VERSION 5.8 ;
BUSBITCHARS "[]" ;
DIVIDERCHAR "/" ;

UNITS
  DATABASE MICRONS 1000 ;
END UNITS

MANUFACTURINGGRID 0.005 ;

LAYER met1
  TYPE ROUTING ;
  DIRECTION HORIZONTAL ;
  PITCH 0.2 ;
  WIDTH 0.1 ;
END met1

SITE core
  CLASS CORE ;
  SIZE 0.2 BY 1.0 ;
END core

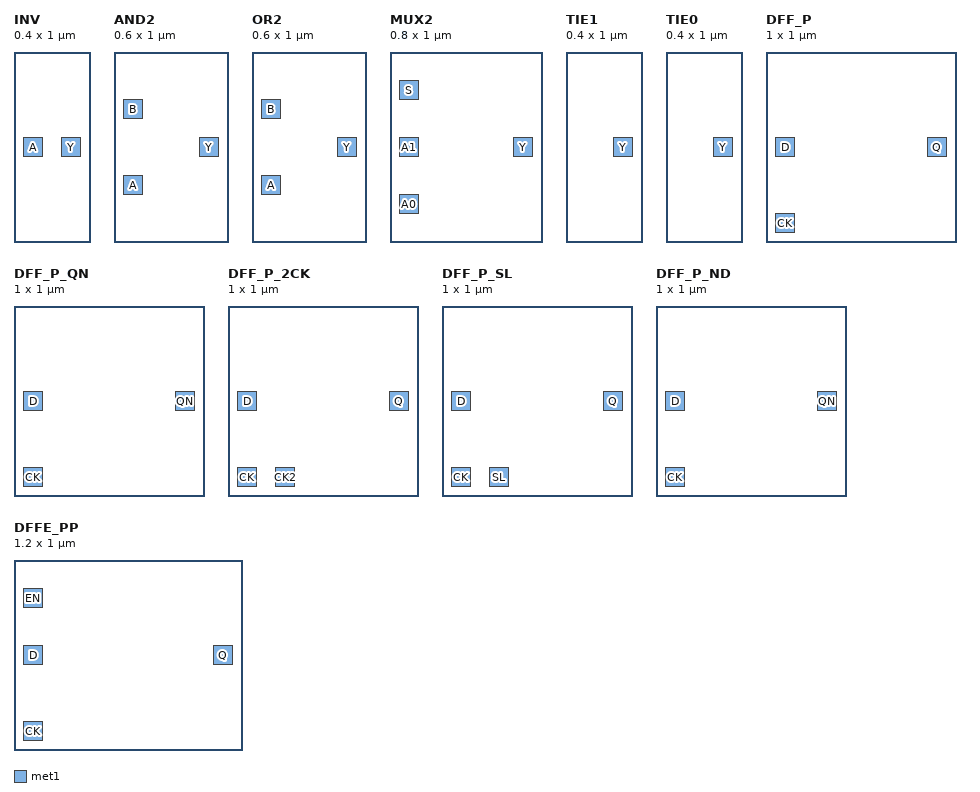
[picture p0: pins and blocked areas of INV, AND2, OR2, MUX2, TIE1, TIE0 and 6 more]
MACRO INV
  CLASS CORE ;
  ORIGIN 0 0 ;
  SIZE 0.4 BY 1.0 ;
  SITE core ;
  PIN A
    DIRECTION INPUT ;
    USE SIGNAL ;
    PORT
      LAYER met1 ;
      RECT 0.05 0.45 0.15 0.55 ;
    END
  END A
  PIN Y
    DIRECTION OUTPUT ;
    USE SIGNAL ;
    PORT
      LAYER met1 ;
      RECT 0.25 0.45 0.35 0.55 ;
    END
  END Y
END INV

MACRO AND2
  CLASS CORE ;
  ORIGIN 0 0 ;
  SIZE 0.6 BY 1.0 ;
  SITE core ;
  PIN A
    DIRECTION INPUT ;
    USE SIGNAL ;
    PORT
      LAYER met1 ;
      RECT 0.05 0.25 0.15 0.35 ;
    END
  END A
  PIN B
    DIRECTION INPUT ;
    USE SIGNAL ;
    PORT
      LAYER met1 ;
      RECT 0.05 0.65 0.15 0.75 ;
    END
  END B
  PIN Y
    DIRECTION OUTPUT ;
    USE SIGNAL ;
    PORT
      LAYER met1 ;
      RECT 0.45 0.45 0.55 0.55 ;
    END
  END Y
END AND2

MACRO OR2
  CLASS CORE ;
  ORIGIN 0 0 ;
  SIZE 0.6 BY 1.0 ;
  SITE core ;
  PIN A
    DIRECTION INPUT ;
    USE SIGNAL ;
    PORT
      LAYER met1 ;
      RECT 0.05 0.25 0.15 0.35 ;
    END
  END A
  PIN B
    DIRECTION INPUT ;
    USE SIGNAL ;
    PORT
      LAYER met1 ;
      RECT 0.05 0.65 0.15 0.75 ;
    END
  END B
  PIN Y
    DIRECTION OUTPUT ;
    USE SIGNAL ;
    PORT
      LAYER met1 ;
      RECT 0.45 0.45 0.55 0.55 ;
    END
  END Y
END OR2
MACRO MUX2
  CLASS CORE ;
  ORIGIN 0 0 ;
  SIZE 0.8 BY 1.0 ;
  SITE core ;
  PIN A0
    DIRECTION INPUT ;
    USE SIGNAL ;
    PORT
      LAYER met1 ;
      RECT 0.05 0.15 0.15 0.25 ;
    END
  END A0
  PIN A1
    DIRECTION INPUT ;
    USE SIGNAL ;
    PORT
      LAYER met1 ;
      RECT 0.05 0.45 0.15 0.55 ;
    END
  END A1
  PIN S
    DIRECTION INPUT ;
    USE SIGNAL ;
    PORT
      LAYER met1 ;
      RECT 0.05 0.75 0.15 0.85 ;
    END
  END S
  PIN Y
    DIRECTION OUTPUT ;
    USE SIGNAL ;
    PORT
      LAYER met1 ;
      RECT 0.65 0.45 0.75 0.55 ;
    END
  END Y
END MUX2


MACRO TIE1
  CLASS CORE ;
  ORIGIN 0 0 ;
  SIZE 0.4 BY 1.0 ;
  SITE core ;
  PIN Y
    DIRECTION OUTPUT ;
    USE SIGNAL ;
    PORT
      LAYER met1 ;
      RECT 0.25 0.45 0.35 0.55 ;
    END
  END Y
END TIE1

MACRO TIE0
  CLASS CORE ;
  ORIGIN 0 0 ;
  SIZE 0.4 BY 1.0 ;
  SITE core ;
  PIN Y
    DIRECTION OUTPUT ;
    USE SIGNAL ;
    PORT
      LAYER met1 ;
      RECT 0.25 0.45 0.35 0.55 ;
    END
  END Y
END TIE0

MACRO DFF_P
  CLASS CORE ;
  ORIGIN 0 0 ;
  SIZE 1.0 BY 1.0 ;
  SITE core ;
  PIN D
    DIRECTION INPUT ;
    USE SIGNAL ;
    PORT
      LAYER met1 ;
      RECT 0.05 0.45 0.15 0.55 ;
    END
  END D
  PIN CK
    DIRECTION INPUT ;
    USE CLOCK ;
    PORT
      LAYER met1 ;
      RECT 0.05 0.05 0.15 0.15 ;
    END
  END CK
  PIN Q
    DIRECTION OUTPUT ;
    USE SIGNAL ;
    PORT
      LAYER met1 ;
      RECT 0.85 0.45 0.95 0.55 ;
    END
  END Q
END DFF_P

MACRO DFF_P_QN
  CLASS CORE ;
  ORIGIN 0 0 ;
  SIZE 1.0 BY 1.0 ;
  SITE core ;
  PIN D
    DIRECTION INPUT ;
    USE SIGNAL ;
    PORT
      LAYER met1 ;
      RECT 0.05 0.45 0.15 0.55 ;
    END
  END D
  PIN CK
    DIRECTION INPUT ;
    USE CLOCK ;
    PORT
      LAYER met1 ;
      RECT 0.05 0.05 0.15 0.15 ;
    END
  END CK
  PIN QN
    DIRECTION OUTPUT ;
    USE SIGNAL ;
    PORT
      LAYER met1 ;
      RECT 0.85 0.45 0.95 0.55 ;
    END
  END QN
END DFF_P_QN

MACRO DFF_P_2CK
  CLASS CORE ;
  ORIGIN 0 0 ;
  SIZE 1.0 BY 1.0 ;
  SITE core ;
  PIN D
    DIRECTION INPUT ;
    USE SIGNAL ;
    PORT
      LAYER met1 ;
      RECT 0.05 0.45 0.15 0.55 ;
    END
  END D
  PIN CK2
    DIRECTION INPUT ;
    USE CLOCK ;
    PORT
      LAYER met1 ;
      RECT 0.25 0.05 0.35 0.15 ;
    END
  END CK2
  PIN CK
    DIRECTION INPUT ;
    USE CLOCK ;
    PORT
      LAYER met1 ;
      RECT 0.05 0.05 0.15 0.15 ;
    END
  END CK
  PIN Q
    DIRECTION OUTPUT ;
    USE SIGNAL ;
    PORT
      LAYER met1 ;
      RECT 0.85 0.45 0.95 0.55 ;
    END
  END Q
END DFF_P_2CK

MACRO DFF_P_SL
  CLASS CORE ;
  ORIGIN 0 0 ;
  SIZE 1.0 BY 1.0 ;
  SITE core ;
  PIN D
    DIRECTION INPUT ;
    USE SIGNAL ;
    PORT
      LAYER met1 ;
      RECT 0.05 0.45 0.15 0.55 ;
    END
  END D
  PIN SL
    DIRECTION INPUT ;
    USE SIGNAL ;
    PORT
      LAYER met1 ;
      RECT 0.25 0.05 0.35 0.15 ;
    END
  END SL
  PIN CK
    DIRECTION INPUT ;
    USE CLOCK ;
    PORT
      LAYER met1 ;
      RECT 0.05 0.05 0.15 0.15 ;
    END
  END CK
  PIN Q
    DIRECTION OUTPUT ;
    USE SIGNAL ;
    PORT
      LAYER met1 ;
      RECT 0.85 0.45 0.95 0.55 ;
    END
  END Q
END DFF_P_SL

MACRO DFF_P_ND
  CLASS CORE ;
  ORIGIN 0 0 ;
  SIZE 1.0 BY 1.0 ;
  SITE core ;
  PIN D
    DIRECTION INPUT ;
    USE SIGNAL ;
    PORT
      LAYER met1 ;
      RECT 0.05 0.45 0.15 0.55 ;
    END
  END D
  PIN CK
    DIRECTION INPUT ;
    USE CLOCK ;
    PORT
      LAYER met1 ;
      RECT 0.05 0.05 0.15 0.15 ;
    END
  END CK
  PIN QN
    DIRECTION OUTPUT ;
    USE SIGNAL ;
    PORT
      LAYER met1 ;
      RECT 0.85 0.45 0.95 0.55 ;
    END
  END QN
END DFF_P_ND

MACRO DFFE_PP
  CLASS CORE ;
  ORIGIN 0 0 ;
  SIZE 1.2 BY 1.0 ;
  SITE core ;
  PIN D
    DIRECTION INPUT ;
    USE SIGNAL ;
    PORT
      LAYER met1 ;
      RECT 0.05 0.45 0.15 0.55 ;
    END
  END D
  PIN EN
    DIRECTION INPUT ;
    USE SIGNAL ;
    PORT
      LAYER met1 ;
      RECT 0.05 0.75 0.15 0.85 ;
    END
  END EN
  PIN CK
    DIRECTION INPUT ;
    USE CLOCK ;
    PORT
      LAYER met1 ;
      RECT 0.05 0.05 0.15 0.15 ;
    END
  END CK
  PIN Q
    DIRECTION OUTPUT ;
    USE SIGNAL ;
    PORT
      LAYER met1 ;
      RECT 1.05 0.45 1.15 0.55 ;
    END
  END Q
END DFFE_PP

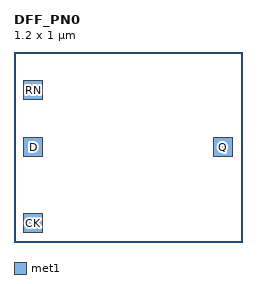
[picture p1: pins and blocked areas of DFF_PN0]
MACRO DFF_PN0
  CLASS CORE ;
  ORIGIN 0 0 ;
  SIZE 1.2 BY 1.0 ;
  SITE core ;
  PIN D
    DIRECTION INPUT ;
    USE SIGNAL ;
    PORT
      LAYER met1 ;
      RECT 0.05 0.45 0.15 0.55 ;
    END
  END D
  PIN RN
    DIRECTION INPUT ;
    USE SIGNAL ;
    PORT
      LAYER met1 ;
      RECT 0.05 0.75 0.15 0.85 ;
    END
  END RN
  PIN CK
    DIRECTION INPUT ;
    USE CLOCK ;
    PORT
      LAYER met1 ;
      RECT 0.05 0.05 0.15 0.15 ;
    END
  END CK
  PIN Q
    DIRECTION OUTPUT ;
    USE SIGNAL ;
    PORT
      LAYER met1 ;
      RECT 1.05 0.45 1.15 0.55 ;
    END
  END Q
END DFF_PN0

END LIBRARY
